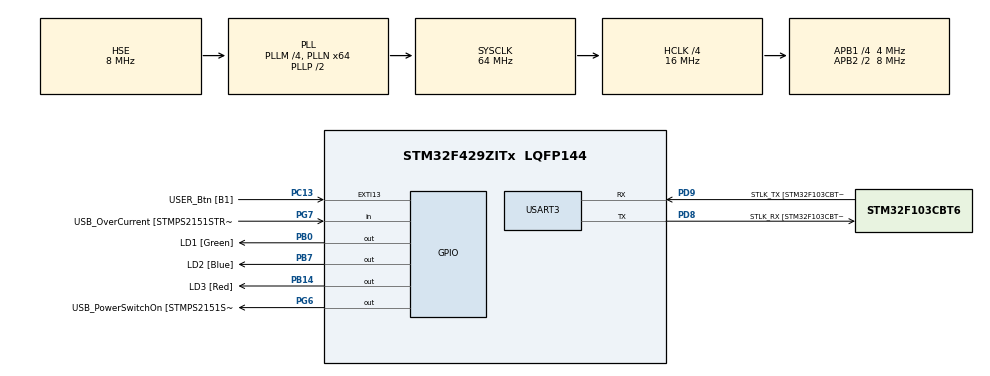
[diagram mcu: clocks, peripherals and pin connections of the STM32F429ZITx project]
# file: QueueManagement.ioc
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Mcu.Family=STM32F4
Mcu.Name=STM32F429ZITx
Mcu.Package=LQFP144
NVIC.PriorityGroup=NVIC_PRIORITYGROUP_4
NVIC.TIM6_DAC_IRQn=true\:15\:0\:false\:false\:true\:false\:true\:true
NVIC.TimeBase=TIM6_DAC_IRQn
NVIC.TimeBaseIP=TIM6
NVIC.USART3_IRQn=true\:6\:0\:true\:false\:true\:true\:true\:true
PA1.GPIO_Label=RMII_REF_CLK [LAN8742A-CZ-TR_REFCLK0]
PA1.Signal=ETH_REF_CLK
PA10.GPIO_Label=USB_ID
PA10.Signal=USB_OTG_FS_ID
PA11.GPIO_Label=USB_DM
PA11.Signal=USB_OTG_FS_DM
PA12.GPIO_Label=USB_DP
PA12.Signal=USB_OTG_FS_DP
PA13.GPIO_Label=TMS
PA13.Signal=SYS_JTMS-SWDIO
PA14.GPIO_Label=TCK
PA14.Signal=SYS_JTCK-SWCLK
PA2.GPIO_Label=RMII_MDIO [LAN8742A-CZ-TR_MDIO]
PA2.Signal=ETH_MDIO
PA7.GPIO_Label=RMII_CRS_DV [LAN8742A-CZ-TR_CRS_DV]
PA7.Signal=ETH_CRS_DV
PA8.GPIO_Label=USB_SOF [TP1]
PA8.Signal=USB_OTG_FS_SOF
PA9.GPIO_Label=USB_VBUS
PA9.Signal=USB_OTG_FS_VBUS
PB0.GPIO_Label=LD1 [Green]
PB0.Signal=GPIO_Output
PB13.GPIO_Label=RMII_TXD1 [LAN8742A-CZ-TR_TXD1]
PB13.Signal=ETH_TXD1
PB14.GPIO_Label=LD3 [Red]
PB14.Signal=GPIO_Output
PB7.GPIO_Label=LD2 [Blue]
PB7.Signal=GPIO_Output
PC1.GPIO_Label=RMII_MDC [LAN8742A-CZ-TR_MDC]
PC1.Signal=ETH_MDC
PC13.GPIO_Label=USER_Btn [B1]
PC13.Signal=GPXTI13
PC14/OSC32_IN.Signal=RCC_OSC32_IN
PC15/OSC32_OUT.Signal=RCC_OSC32_OUT
PC4.GPIO_Label=RMII_RXD0 [LAN8742A-CZ-TR_RXD0]
PC4.Signal=ETH_RXD0
PC5.GPIO_Label=RMII_RXD1 [LAN8742A-CZ-TR_RXD1]
PC5.Signal=ETH_RXD1
PD8.GPIO_Label=STLK_RX [STM32F103CBT6_PA3]
PD8.Mode=Asynchronous
PD8.Signal=USART3_TX
PD9.GPIO_Label=STLK_TX [STM32F103CBT6_PA2]
PD9.Mode=Asynchronous
PD9.Signal=USART3_RX
PG11.GPIO_Label=RMII_TX_EN [LAN8742A-CZ-TR_TXEN]
PG11.Signal=ETH_TX_EN
PG13.GPIO_Label=RMII_TXD0 [LAN8742A-CZ-TR_TXD0]
PG13.Signal=ETH_TXD0
PG6.GPIO_Label=USB_PowerSwitchOn [STMPS2151STR_EN]
PG6.Signal=GPIO_Output
PG7.GPIO_Label=USB_OverCurrent [STMPS2151STR_FAULT]
PG7.Signal=GPIO_Input
PH0/OSC_IN.GPIO_Label=MCO [STM32F103CBT6_PA8]
PH0/OSC_IN.Mode=HSE-External-Clock-Source
PH0/OSC_IN.Signal=RCC_OSC_IN
PH1/OSC_OUT.Mode=HSE-External-Clock-Source
PH1/OSC_OUT.Signal=RCC_OSC_OUT
ProjectManager.HeapSize=0x200
ProjectManager.StackSize=0x400
ProjectManager.TargetToolchain=STM32CubeIDE
RCC.48MHZClocksFreq_Value=32000000
RCC.AHBCLKDivider=RCC_SYSCLK_DIV4
RCC.AHBFreq_Value=16000000
RCC.APB1CLKDivider=RCC_HCLK_DIV4
RCC.APB1Freq_Value=4000000
RCC.APB1TimFreq_Value=8000000
RCC.APB2CLKDivider=RCC_HCLK_DIV2
RCC.APB2Freq_Value=8000000
RCC.APB2TimFreq_Value=16000000
RCC.CortexFreq_Value=16000000
RCC.HCLKFreq_Value=16000000
RCC.HSE_VALUE=8000000
RCC.HSI_VALUE=16000000
RCC.LSE_VALUE=32768
RCC.PLLM=4
RCC.PLLMUL=RCC_PLL_MUL9
RCC.PLLN=64
RCC.PLLSourceVirtual=RCC_PLLSOURCE_HSE
RCC.PRESCALERUSB=RCC_USBCLKSOURCE_PLL_DIV1_5
RCC.SYSCLKFreq_VALUE=64000000
RCC.SYSCLKSource=RCC_SYSCLKSOURCE_PLLCLK
RCC.SYSCLKSourceVirtual=RCC_SYSCLKSOURCE_PLLCLK
RCC.USBFreq_Value=48000000
RCC.VCOOutputFreq_Value=128000000
RTC.HourFormat=RTC_HOURFORMAT_12
USART3.VirtualMode=VM_ASYNC
VP_RTC_VS_RTC_Activate.Mode=RTC_Enabled
VP_SYS_VS_tim6.Mode=TIM6
board=NUCLEO-F429ZI

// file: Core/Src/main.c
/* USER CODE BEGIN Header */
/**
  ******************************************************************************
  * @file           : main.c
  * @brief          : Main program body
  ******************************************************************************
  * @attention
  *
  * Copyright (c) 2022 STMicroelectronics.
  * All rights reserved.
  *
  * This software is licensed under terms that can be found in the LICENSE file
  * in the root directory of this software component.
  * If no LICENSE file comes with this software, it is provided AS-IS.
  *
  ******************************************************************************
  */
/* USER CODE END Header */
#include "main.h"

RTC_HandleTypeDef hrtc;

UART_HandleTypeDef huart3;

void SystemClock_Config(void);
static void MX_GPIO_Init(void);
static void MX_RTC_Init(void);
static void MX_USART3_UART_Init(void);

/* USER CODE BEGIN 0 */

TaskHandle_t menuTask_handle;
TaskHandle_t printTask_handle;
TaskHandle_t ledTask_handle;
TaskHandle_t rtcTask_handle;
TaskHandle_t cmdTask_handle;

QueueHandle_t q_data;
QueueHandle_t print_queue;

uint8_t user_data;
State_t curr_state = STATE_MainMenu;

TimerHandle_t timer_handle[4];

TimerHandle_t rprting_timer;

/* USER CODE END 0 */

int main(void)
{

  /* MCU Configuration--------------------------------------------------------*/

  /* Reset of all peripherals, Initializes the Flash interface and the Systick. */
  HAL_Init();

  /* Configure the system clock */
  SystemClock_Config();

  /* Initialize all configured peripherals */
  MX_GPIO_Init();
  MX_RTC_Init();
  MX_USART3_UART_Init();
  /* USER CODE BEGIN 2 */

  lcd_init();

  configASSERT(xTaskCreate(MenuTask_Handler, "Menu Task", 250, NULL, 2, &menuTask_handle) == pdPASS);

  configASSERT(xTaskCreate(CMDTask_Handler, "CMD Task", 250, NULL, 2, &cmdTask_handle) == pdPASS);

  configASSERT(xTaskCreate(PrintTask_Handler, "Print Task", 250, NULL, 2, &printTask_handle) == pdPASS);

  configASSERT(xTaskCreate(LEDTask_Handler, "LED Task", 250, NULL, 2, &ledTask_handle) == pdPASS);

  configASSERT(xTaskCreate(RTCTask_Handler, "RTC Task", 250, NULL, 2, &rtcTask_handle) == pdPASS);

  q_data = xQueueCreate(10, sizeof(char));

  configASSERT(q_data != NULL);

  print_queue = xQueueCreate(10, sizeof(size_t));

  configASSERT(print_queue != NULL);

  for (uint8_t i = 0; i < 4; i++)
  {
	 timer_handle[i] = xTimerCreate("LED Timer", pdMS_TO_TICKS(500), pdTRUE, (void*)(i+1), LedEffectsCallback);
  }

  rprting_timer = xTimerCreate("Reporting Timer", pdMS_TO_TICKS(1000), pdTRUE, NULL, RTCReportCallback);

  if (HAL_UART_Receive_IT(&huart3, &user_data, 1) != HAL_OK)
  {
	  Error_Handler();
  }

  vTaskStartScheduler();

  /* USER CODE END 2 */

  /* Infinite loop */
  while (1)
  {

  }
}

void SystemClock_Config(void)
{
  RCC_OscInitTypeDef RCC_OscInitStruct = {0};
  RCC_ClkInitTypeDef RCC_ClkInitStruct = {0};

  /** Configure the main internal regulator output voltage
  */
  __HAL_RCC_PWR_CLK_ENABLE();
  __HAL_PWR_VOLTAGESCALING_CONFIG(PWR_REGULATOR_VOLTAGE_SCALE3);

  /** Initializes the RCC Oscillators according to the specified parameters
  * in the RCC_OscInitTypeDef structure.
  */
  RCC_OscInitStruct.OscillatorType = RCC_OSCILLATORTYPE_LSI|RCC_OSCILLATORTYPE_HSE;
  RCC_OscInitStruct.HSEState = RCC_HSE_BYPASS;
  RCC_OscInitStruct.LSIState = RCC_LSI_ON;
  RCC_OscInitStruct.PLL.PLLState = RCC_PLL_ON;
  RCC_OscInitStruct.PLL.PLLSource = RCC_PLLSOURCE_HSE;
  RCC_OscInitStruct.PLL.PLLM = 4;
  RCC_OscInitStruct.PLL.PLLN = 64;
  RCC_OscInitStruct.PLL.PLLP = RCC_PLLP_DIV2;
  RCC_OscInitStruct.PLL.PLLQ = 4;
  if (HAL_RCC_OscConfig(&RCC_OscInitStruct) != HAL_OK)
  {
    Error_Handler();
  }

  /** Initializes the CPU, AHB and APB buses clocks
  */
  RCC_ClkInitStruct.ClockType = RCC_CLOCKTYPE_HCLK|RCC_CLOCKTYPE_SYSCLK
                              |RCC_CLOCKTYPE_PCLK1|RCC_CLOCKTYPE_PCLK2;
  RCC_ClkInitStruct.SYSCLKSource = RCC_SYSCLKSOURCE_PLLCLK;
  RCC_ClkInitStruct.AHBCLKDivider = RCC_SYSCLK_DIV4;
  RCC_ClkInitStruct.APB1CLKDivider = RCC_HCLK_DIV4;
  RCC_ClkInitStruct.APB2CLKDivider = RCC_HCLK_DIV2;

  if (HAL_RCC_ClockConfig(&RCC_ClkInitStruct, FLASH_LATENCY_0) != HAL_OK)
  {
    Error_Handler();
  }
}

static void MX_RTC_Init(void)
{

  /** Initialize RTC Only
  */
  hrtc.Instance = RTC;
  hrtc.Init.HourFormat = RTC_HOURFORMAT_12;
  hrtc.Init.AsynchPrediv = 127;
  hrtc.Init.SynchPrediv = 255;
  hrtc.Init.OutPut = RTC_OUTPUT_DISABLE;
  hrtc.Init.OutPutPolarity = RTC_OUTPUT_POLARITY_HIGH;
  hrtc.Init.OutPutType = RTC_OUTPUT_TYPE_OPENDRAIN;
  if (HAL_RTC_Init(&hrtc) != HAL_OK)
  {
    Error_Handler();
  }

}

static void MX_USART3_UART_Init(void)
{

  huart3.Instance = USART3;
  huart3.Init.BaudRate = 115200;
  huart3.Init.WordLength = UART_WORDLENGTH_8B;
  huart3.Init.StopBits = UART_STOPBITS_1;
  huart3.Init.Parity = UART_PARITY_NONE;
  huart3.Init.Mode = UART_MODE_TX_RX;
  huart3.Init.HwFlowCtl = UART_HWCONTROL_NONE;
  huart3.Init.OverSampling = UART_OVERSAMPLING_16;
  if (HAL_UART_Init(&huart3) != HAL_OK)
  {
    Error_Handler();
  }

}

static void MX_GPIO_Init(void)
{
  GPIO_InitTypeDef GPIO_InitStruct = {0};

  /* GPIO Ports Clock Enable */
  __HAL_RCC_GPIOC_CLK_ENABLE();
  __HAL_RCC_GPIOH_CLK_ENABLE();
  __HAL_RCC_GPIOA_CLK_ENABLE();
  __HAL_RCC_GPIOB_CLK_ENABLE();
  __HAL_RCC_GPIOD_CLK_ENABLE();
  __HAL_RCC_GPIOG_CLK_ENABLE();

  /*Configure GPIO pin Output Level */
  HAL_GPIO_WritePin(GPIOB, LD1_Pin|LD3_Pin|LD2_Pin, GPIO_PIN_RESET);

  /*Configure GPIO pin Output Level */
  HAL_GPIO_WritePin(USB_PowerSwitchOn_GPIO_Port, USB_PowerSwitchOn_Pin, GPIO_PIN_RESET);

  /*Configure GPIO pin : USER_Btn_Pin */
  GPIO_InitStruct.Pin = USER_Btn_Pin;
  GPIO_InitStruct.Mode = GPIO_MODE_IT_RISING;
  GPIO_InitStruct.Pull = GPIO_NOPULL;
  HAL_GPIO_Init(USER_Btn_GPIO_Port, &GPIO_InitStruct);

  /*Configure GPIO pins : RMII_MDC_Pin RMII_RXD0_Pin RMII_RXD1_Pin */
  GPIO_InitStruct.Pin = RMII_MDC_Pin|RMII_RXD0_Pin|RMII_RXD1_Pin;
  GPIO_InitStruct.Mode = GPIO_MODE_AF_PP;
  GPIO_InitStruct.Pull = GPIO_NOPULL;
  GPIO_InitStruct.Speed = GPIO_SPEED_FREQ_VERY_HIGH;
  GPIO_InitStruct.Alternate = GPIO_AF11_ETH;
  HAL_GPIO_Init(GPIOC, &GPIO_InitStruct);

  /*Configure GPIO pins : RMII_REF_CLK_Pin RMII_MDIO_Pin RMII_CRS_DV_Pin */
  GPIO_InitStruct.Pin = RMII_REF_CLK_Pin|RMII_MDIO_Pin|RMII_CRS_DV_Pin;
  GPIO_InitStruct.Mode = GPIO_MODE_AF_PP;
  GPIO_InitStruct.Pull = GPIO_NOPULL;
  GPIO_InitStruct.Speed = GPIO_SPEED_FREQ_VERY_HIGH;
  GPIO_InitStruct.Alternate = GPIO_AF11_ETH;
  HAL_GPIO_Init(GPIOA, &GPIO_InitStruct);

  /*Configure GPIO pins : LD1_Pin LD3_Pin LD2_Pin */
  GPIO_InitStruct.Pin = LD1_Pin|LD3_Pin|LD2_Pin;
  GPIO_InitStruct.Mode = GPIO_MODE_OUTPUT_PP;
  GPIO_InitStruct.Pull = GPIO_NOPULL;
  GPIO_InitStruct.Speed = GPIO_SPEED_FREQ_LOW;
  HAL_GPIO_Init(GPIOB, &GPIO_InitStruct);

  /*Configure GPIO pin : RMII_TXD1_Pin */
  GPIO_InitStruct.Pin = RMII_TXD1_Pin;
  GPIO_InitStruct.Mode = GPIO_MODE_AF_PP;
  GPIO_InitStruct.Pull = GPIO_NOPULL;
  GPIO_InitStruct.Speed = GPIO_SPEED_FREQ_VERY_HIGH;
  GPIO_InitStruct.Alternate = GPIO_AF11_ETH;
  HAL_GPIO_Init(RMII_TXD1_GPIO_Port, &GPIO_InitStruct);

  /*Configure GPIO pin : USB_PowerSwitchOn_Pin */
  GPIO_InitStruct.Pin = USB_PowerSwitchOn_Pin;
  GPIO_InitStruct.Mode = GPIO_MODE_OUTPUT_PP;
  GPIO_InitStruct.Pull = GPIO_NOPULL;
  GPIO_InitStruct.Speed = GPIO_SPEED_FREQ_LOW;
  HAL_GPIO_Init(USB_PowerSwitchOn_GPIO_Port, &GPIO_InitStruct);

  /*Configure GPIO pin : USB_OverCurrent_Pin */
  GPIO_InitStruct.Pin = USB_OverCurrent_Pin;
  GPIO_InitStruct.Mode = GPIO_MODE_INPUT;
  GPIO_InitStruct.Pull = GPIO_NOPULL;
  HAL_GPIO_Init(USB_OverCurrent_GPIO_Port, &GPIO_InitStruct);

  /*Configure GPIO pins : USB_SOF_Pin USB_ID_Pin USB_DM_Pin USB_DP_Pin */
  GPIO_InitStruct.Pin = USB_SOF_Pin|USB_ID_Pin|USB_DM_Pin|USB_DP_Pin;
  GPIO_InitStruct.Mode = GPIO_MODE_AF_PP;
  GPIO_InitStruct.Pull = GPIO_NOPULL;
  GPIO_InitStruct.Speed = GPIO_SPEED_FREQ_VERY_HIGH;
  GPIO_InitStruct.Alternate = GPIO_AF10_OTG_FS;
  HAL_GPIO_Init(GPIOA, &GPIO_InitStruct);

  /*Configure GPIO pin : USB_VBUS_Pin */
  GPIO_InitStruct.Pin = USB_VBUS_Pin;
  GPIO_InitStruct.Mode = GPIO_MODE_INPUT;
  GPIO_InitStruct.Pull = GPIO_NOPULL;
  HAL_GPIO_Init(USB_VBUS_GPIO_Port, &GPIO_InitStruct);

  /*Configure GPIO pins : RMII_TX_EN_Pin RMII_TXD0_Pin */
  GPIO_InitStruct.Pin = RMII_TX_EN_Pin|RMII_TXD0_Pin;
  GPIO_InitStruct.Mode = GPIO_MODE_AF_PP;
  GPIO_InitStruct.Pull = GPIO_NOPULL;
  GPIO_InitStruct.Speed = GPIO_SPEED_FREQ_VERY_HIGH;
  GPIO_InitStruct.Alternate = GPIO_AF11_ETH;
  HAL_GPIO_Init(GPIOG, &GPIO_InitStruct);

  /* LCD pins configuration */
  GPIO_InitStruct.Pin = GPIO_PIN_11 | GPIO_PIN_12 | GPIO_PIN_13 | GPIO_PIN_4
		  	  | GPIO_PIN_5 | GPIO_PIN_6 | GPIO_PIN_7;
  GPIO_InitStruct.Mode = GPIO_MODE_OUTPUT_PP;
  GPIO_InitStruct.Pull = GPIO_NOPULL;
  GPIO_InitStruct.Speed = GPIO_SPEED_FREQ_VERY_HIGH;
  HAL_GPIO_Init(GPIOD, &GPIO_InitStruct);

}

/* USER CODE BEGIN 4 */

void HAL_UART_RxCpltCallback(UART_HandleTypeDef *huart)
{
	//for (uint32_t i = 0; i < 4000; i++);

	uint8_t dummy_variable;
	// checking if the queue is full or not
	if (! xQueueIsQueueFullFromISR(q_data))
	{
		// queue is not full, so, enqueue the newly received data byte
		xQueueSendFromISR(q_data, (void*)&user_data, NULL);
	}
	else
	{
		// queue is full, so, check for the carriage return  character
		if (user_data == '\n')
		{
			xQueueReceiveFromISR(q_data, (void*)&dummy_variable, NULL);
			xQueueSendFromISR(q_data, (void*)"\n", NULL);
		}
	}

	if (user_data == '\n')
		xTaskNotifyFromISR(cmdTask_handle, 0, eNoAction, NULL);

	if (HAL_UART_Receive_IT(&huart3, &user_data, 1) != HAL_OK)
	{
		Error_Handler();
	}
}

// timer expired callback function
void LedEffectsCallback(TimerHandle_t timer_h)
{
	int id;
	id = (uint32_t)pvTimerGetTimerID(timer_h);

	switch(id)
	{
	case 1:
	{
		led_action1();
		break;
	}
	case 2:
	{
		led_action2();
		break;
	}
	case 3:
	{
		led_action3();
		break;
	}
	case 4:
	{
		led_action4();
		break;
	}
	}
}

void RTCReportCallback(TimerHandle_t rprt_timer)
{
	show_dateTime_LCD();
}

/* USER CODE END 4 */

void HAL_TIM_PeriodElapsedCallback(TIM_HandleTypeDef *htim)
{
  if (htim->Instance == TIM6) {
    HAL_IncTick();
  }
}

void Error_Handler(void)
{
  __disable_irq();
  while (1)
  {
  }
}
